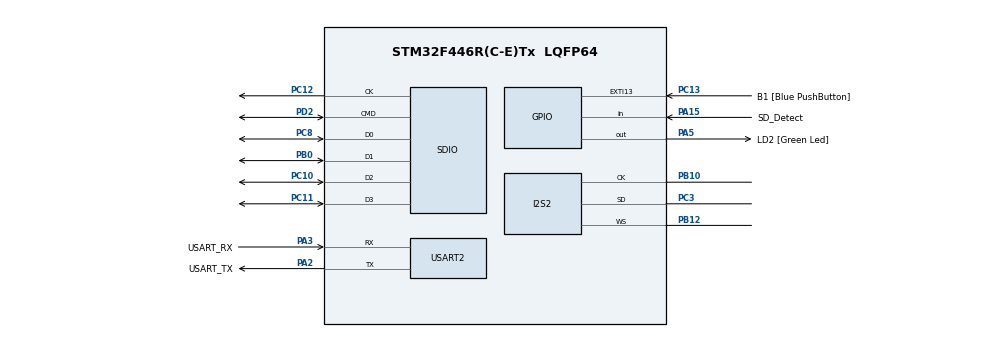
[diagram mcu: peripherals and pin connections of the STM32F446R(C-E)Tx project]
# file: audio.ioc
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Dma.Request0=SPI2_RX
Dma.Request1=USART2_TX
Dma.SPI2_RX.0.Direction=DMA_PERIPH_TO_MEMORY
Dma.SPI2_RX.0.FIFOMode=DMA_FIFOMODE_DISABLE
Dma.SPI2_RX.0.Instance=DMA1_Stream3
Dma.SPI2_RX.0.MemDataAlignment=DMA_MDATAALIGN_HALFWORD
Dma.SPI2_RX.0.MemInc=DMA_MINC_ENABLE
Dma.SPI2_RX.0.Mode=DMA_CIRCULAR
Dma.SPI2_RX.0.PeriphDataAlignment=DMA_PDATAALIGN_HALFWORD
Dma.SPI2_RX.0.PeriphInc=DMA_PINC_DISABLE
Dma.SPI2_RX.0.Priority=DMA_PRIORITY_LOW
Dma.USART2_TX.1.Direction=DMA_MEMORY_TO_PERIPH
Dma.USART2_TX.1.FIFOMode=DMA_FIFOMODE_DISABLE
Dma.USART2_TX.1.Instance=DMA1_Stream6
Dma.USART2_TX.1.MemDataAlignment=DMA_MDATAALIGN_HALFWORD
Dma.USART2_TX.1.MemInc=DMA_MINC_ENABLE
Dma.USART2_TX.1.Mode=DMA_CIRCULAR
Dma.USART2_TX.1.PeriphDataAlignment=DMA_PDATAALIGN_HALFWORD
Dma.USART2_TX.1.PeriphInc=DMA_PINC_DISABLE
Dma.USART2_TX.1.Priority=DMA_PRIORITY_LOW
FATFS.BSP.number=1
FATFS0.BSP.STBoard=false
FATFS0.BSP.api=Unknown
FATFS0.BSP.instance=PA15
FATFS0.BSP.ip=GPIO
FATFS0.BSP.mode=Input
FATFS0.BSP.name=Detect_SDIO
FATFS0.BSP.solution=PA15
I2S2.AudioFreq=I2S_AUDIOFREQ_32K
I2S2.DataFormat=I2S_DATAFORMAT_16B_EXTENDED
I2S2.ErrorAudioFreq=-0.26 %
I2S2.FullDuplexMode=I2S_FULLDUPLEXMODE_DISABLE
I2S2.Instance=SPI$Index
I2S2.Mode=I2S_MODE_MASTER_RX
I2S2.RealAudioFreq=31.914 KHz
I2S2.VirtualMode=I2S_MODE_MASTER
Mcu.Family=STM32F4
Mcu.Name=STM32F446R(C-E)Tx
Mcu.Package=LQFP64
NVIC.DMA1_Stream3_IRQn=true\:0\:0\:false\:false\:true\:false\:true\:true
NVIC.DMA1_Stream6_IRQn=true\:0\:0\:false\:false\:true\:false\:true\:true
NVIC.EXTI15_10_IRQn=true\:0\:0\:false\:false\:true\:true\:true\:true
NVIC.PriorityGroup=NVIC_PRIORITYGROUP_0
NVIC.USART2_IRQn=true\:0\:0\:false\:false\:true\:true\:true\:true
PA13.GPIO_Label=TMS
PA13.Mode=Serial_Wire
PA13.Signal=SYS_JTMS-SWDIO
PA14.GPIO_Label=TCK
PA14.Mode=Serial_Wire
PA14.Signal=SYS_JTCK-SWCLK
PA15.GPIO_Label=SD_Detect
PA15.Signal=GPIO_Input
PA2.GPIO_Label=USART_TX
PA2.Mode=Asynchronous
PA2.Signal=USART2_TX
PA3.GPIO_Label=USART_RX
PA3.Mode=Asynchronous
PA3.Signal=USART2_RX
PA5.GPIO_Label=LD2 [Green Led]
PA5.Signal=GPIO_Output
PB0.Mode=SD_4_bits_Wide_bus
PB0.Signal=SDIO_D1
PB10.Mode=Half_Duplex_Master
PB10.Signal=I2S2_CK
PB12.Mode=Half_Duplex_Master
PB12.Signal=I2S2_WS
PB3.GPIO_Label=SWO
PB3.Signal=SYS_JTDO-SWO
PC10.Mode=SD_4_bits_Wide_bus
PC10.Signal=SDIO_D2
PC11.Mode=SD_4_bits_Wide_bus
PC11.Signal=SDIO_D3
PC12.Mode=SD_4_bits_Wide_bus
PC12.Signal=SDIO_CK
PC13.GPIO_Label=B1 [Blue PushButton]
PC13.GPIO_ModeDefaultEXTI=GPIO_MODE_IT_RISING
PC13.Signal=GPXTI13
PC14-OSC32_IN.Mode=LSE-External-Oscillator
PC14-OSC32_IN.Signal=RCC_OSC32_IN
PC15-OSC32_OUT.Mode=LSE-External-Oscillator
PC15-OSC32_OUT.Signal=RCC_OSC32_OUT
PC3.Mode=Half_Duplex_Master
PC3.Signal=I2S2_SD
PC8.Mode=SD_4_bits_Wide_bus
PC8.Signal=SDIO_D0
PD2.Mode=SD_4_bits_Wide_bus
PD2.Signal=SDIO_CMD
PH0-OSC_IN.Mode=HSE-External-Oscillator
PH0-OSC_IN.Signal=RCC_OSC_IN
PH1-OSC_OUT.Mode=HSE-External-Oscillator
PH1-OSC_OUT.Signal=RCC_OSC_OUT
ProjectManager.HeapSize=0x200
ProjectManager.StackSize=0x400
ProjectManager.TargetToolchain=STM32CubeIDE
RCC.48MHZClocksFreq_Value=84000000
RCC.AHBFreq_Value=160000000
RCC.APB1CLKDivider=RCC_HCLK_DIV4
RCC.APB1Freq_Value=40000000
RCC.APB1TimFreq_Value=80000000
RCC.APB2CLKDivider=RCC_HCLK_DIV2
RCC.APB2Freq_Value=80000000
RCC.APB2TimFreq_Value=160000000
RCC.CortexFreq_Value=160000000
RCC.FLatency-AdvancedSettings=FLASH_LATENCY_5
RCC.HCLKFreq_Value=160000000
RCC.HSE_VALUE=8000000
RCC.HSI_VALUE=16000000
RCC.PLLM=8
RCC.PLLN=160
RCC.PLLQ=7
RCC.SYSCLKFreq_VALUE=160000000
RCC.SYSCLKSource=RCC_SYSCLKSOURCE_PLLCLK
RCC.USBFreq_Value=45714285.71428572
RCC.VCOOutputFreq_Value=320000000
SDIO.ClockDiv=8
STMicroelectronics.X-CUBE-ALGOBUILD.1.3.0.LibraryCcDSPOoLibraryJjDSPOoLibrary=true
USART2.VirtualMode=VM_ASYNC
VP_FATFS_VS_SDIO.Mode=SDIO
VP_STMicroelectronics.X-CUBE-ALGOBUILD_VS_DSPOoLibraryJjLibrary_1.3.0_1.3.0.Mode=DSPOoLibraryJjLibrary
board=NUCLEO-F446RE

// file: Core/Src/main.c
/* USER CODE BEGIN Header */
/**
  ******************************************************************************
  * @file           : main.c
  * @brief          : Main program body
  ******************************************************************************
  * @attention
  *
  * Copyright (c) 2022 STMicroelectronics.
  * All rights reserved.
  *
  * This software is licensed under terms that can be found in the LICENSE file
  * in the root directory of this software component.
  * If no LICENSE file comes with this software, it is provided AS-IS.
  *
  ******************************************************************************
  */
/* USER CODE END Header */
#include "main.h"
#include "fatfs.h"

/* USER CODE BEGIN Includes */
#include "stdio.h"

#include "arm_math.h"
#include "audio_sd.h"
/* USER CODE END Includes */

 I2S_HandleTypeDef hi2s2;
DMA_HandleTypeDef hdma_spi2_rx;

SD_HandleTypeDef hsd;

UART_HandleTypeDef huart2;
DMA_HandleTypeDef hdma_usart2_tx;

/* USER CODE BEGIN PV */
int16_t data_i2s[WAV_WRITE_SAMPLE_COUNT];
float32_t mic1_data1[WAV_WRITE_SAMPLE_COUNT / 4],
	mic1_data2[WAV_WRITE_SAMPLE_COUNT / 4];
float32_t data_out_fft1[WAV_WRITE_SAMPLE_COUNT / 4],
	data_out_fft2[WAV_WRITE_SAMPLE_COUNT / 4];
volatile int16_t sample_i2s;
volatile uint8_t button_flag, start_stop_recording;
volatile uint8_t  half_i2s, full_i2s;
arm_rfft_fast_instance_f32 fft_audio_instance;
/* USER CODE END PV */

void SystemClock_Config(void);
static void MX_GPIO_Init(void);
static void MX_DMA_Init(void);
static void MX_I2S2_Init(void);
static void MX_SDIO_SD_Init(void);
static void MX_USART2_UART_Init(void);

int main(void)
{
  /* USER CODE BEGIN 1 */
uint8_t uart_counter;
  /* USER CODE END 1 */

  /* MCU Configuration--------------------------------------------------------*/

  /* Reset of all peripherals, Initializes the Flash interface and the Systick. */
  HAL_Init();

  /* Configure the system clock */
  SystemClock_Config();

  /* Initialize all configured peripherals */
  MX_GPIO_Init();
  MX_DMA_Init();
  MX_I2S2_Init();
  MX_SDIO_SD_Init();
  MX_FATFS_Init();
  MX_USART2_UART_Init();
  /* USER CODE BEGIN 2 */
  HAL_I2S_DMAStop(&hi2s2);
  HAL_Delay(500);
  //	Initializing FFT. We apply FFT for the first microphone and half of the buffer.
  //	Therefore we divide by four: WAV_WRITE_SAMPLE_COUNT / 4
  arm_rfft_fast_init_f32(&fft_audio_instance, WAV_WRITE_SAMPLE_COUNT / 4);
  /* USER CODE END 2 */

  /* Infinite loop */
  /* USER CODE BEGIN WHILE */
  while (1)
  {
	  // when button is pressed
	  if(button_flag)
	  {
		  //	stop recording: stop I2S DMA
		  if(start_stop_recording)
		  {
			  HAL_I2S_DMAStop(&hi2s2);
			  start_stop_recording = 0;
			  half_i2s = 0;
			  full_i2s = 0;
			  printf("stop recording \n");
		  }

		  // start recording: start DMA
		  else
		  {
			  start_stop_recording = 1;
			  printf("start_recording");
			  HAL_I2S_Receive_DMA(&hi2s2, (uint16_t *)data_i2s, sizeof(data_i2s)/2);
		  }
		  button_flag = 0;
	  }
    /* USER CODE END WHILE */

    /* USER CODE BEGIN 3 */
	  // When half of the buffer is full
	  if(start_stop_recording == 1 && half_i2s == 1)
	  {
		  // extracting the data of the first microphone
		  for(int i = 0; i < WAV_WRITE_SAMPLE_COUNT / 4; i++ )
		  {
			  mic1_data1[i] = (float32_t)data_i2s[i * 2];
		  }
		  // apply FFT
		  arm_rfft_fast_f32(&fft_audio_instance, mic1_data1, data_out_fft1, 0);
		  // extract absolute values by computing the magnitude of the complex numbers
		  // Pay attention that after this operation, half of the buffer possesses the magnitudes
		  arm_cmplx_mag_f32(
				  data_out_fft1,
				  data_out_fft1,
				  WAV_WRITE_SAMPLE_COUNT / 8);
		  // bias removal
		  data_out_fft1[0] = 0;
		  if(full_i2s == 1)
		  {
			  printf("d \n");
		  }
		  uart_counter++;
		  //	setting ">>>>" to indicate the end of the buffer
	  	  data_out_fft1[WAV_WRITE_SAMPLE_COUNT / 8] = ('>'<<24|'>'<<16|'>'<<8|'>');

	  if (uart_counter == 30)
		  {
			  printf("uart start\n");
			  uart_counter = 0;
			  //	sending only half of the buffer
			  HAL_UART_Transmit_DMA(&huart2, (uint8_t *)&data_out_fft1, sizeof(data_out_fft1) / 2 + 4);
		  }
		  half_i2s = 0;
	  }

	  //	THe buffer is full
	  if(start_stop_recording == 1 && full_i2s == 1)
	  {
		  // extracting the data of the first microphone
		  for(int i = 0; i < WAV_WRITE_SAMPLE_COUNT / 4; i++ )
		  {
			  mic1_data2[i] = (float32_t)data_i2s[i * 2 +
												WAV_WRITE_SAMPLE_COUNT / 2];
		  }
		  // applying FFT
		  arm_rfft_fast_f32(&fft_audio_instance, mic1_data2, data_out_fft2, 0);
		  // extract absolute values by computing the magnitude of the complex numbers
		  // Pay attention that after this operation, half of the buffer possesses the magnitudes
		  arm_cmplx_mag_f32(
				  data_out_fft2,
				  data_out_fft2,
				  WAV_WRITE_SAMPLE_COUNT / 8);
		  // bias removal
		  data_out_fft2[0] = 0;
		  if(half_i2s == 1)
		  {
			  printf("d \n");
		  }
		  full_i2s = 0;
	  }
  }
  /* USER CODE END 3 */
}

void SystemClock_Config(void)
{
  RCC_OscInitTypeDef RCC_OscInitStruct = {0};
  RCC_ClkInitTypeDef RCC_ClkInitStruct = {0};

  /** Configure the main internal regulator output voltage
  */
  __HAL_RCC_PWR_CLK_ENABLE();
  __HAL_PWR_VOLTAGESCALING_CONFIG(PWR_REGULATOR_VOLTAGE_SCALE1);

  /** Initializes the RCC Oscillators according to the specified parameters
  * in the RCC_OscInitTypeDef structure.
  */
  RCC_OscInitStruct.OscillatorType = RCC_OSCILLATORTYPE_HSI;
  RCC_OscInitStruct.HSIState = RCC_HSI_ON;
  RCC_OscInitStruct.HSICalibrationValue = RCC_HSICALIBRATION_DEFAULT;
  RCC_OscInitStruct.PLL.PLLState = RCC_PLL_ON;
  RCC_OscInitStruct.PLL.PLLSource = RCC_PLLSOURCE_HSI;
  RCC_OscInitStruct.PLL.PLLM = 8;
  RCC_OscInitStruct.PLL.PLLN = 168;
  RCC_OscInitStruct.PLL.PLLP = RCC_PLLP_DIV2;
  RCC_OscInitStruct.PLL.PLLQ = 7;
  if (HAL_RCC_OscConfig(&RCC_OscInitStruct) != HAL_OK)
  {
    Error_Handler();
  }

  /** Initializes the CPU, AHB and APB buses clocks
  */
  RCC_ClkInitStruct.ClockType = RCC_CLOCKTYPE_HCLK|RCC_CLOCKTYPE_SYSCLK
                              |RCC_CLOCKTYPE_PCLK1|RCC_CLOCKTYPE_PCLK2;
  RCC_ClkInitStruct.SYSCLKSource = RCC_SYSCLKSOURCE_PLLCLK;
  RCC_ClkInitStruct.AHBCLKDivider = RCC_SYSCLK_DIV1;
  RCC_ClkInitStruct.APB1CLKDivider = RCC_HCLK_DIV4;
  RCC_ClkInitStruct.APB2CLKDivider = RCC_HCLK_DIV2;

  if (HAL_RCC_ClockConfig(&RCC_ClkInitStruct, FLASH_LATENCY_5) != HAL_OK)
  {
    Error_Handler();
  }
}

static void MX_I2S2_Init(void)
{

  hi2s2.Instance = SPI2;
  hi2s2.Init.Mode = I2S_MODE_MASTER_RX;
  hi2s2.Init.Standard = I2S_STANDARD_PHILIPS;
  hi2s2.Init.DataFormat = I2S_DATAFORMAT_16B_EXTENDED;
  hi2s2.Init.MCLKOutput = I2S_MCLKOUTPUT_DISABLE;
  hi2s2.Init.AudioFreq = I2S_AUDIOFREQ_32K;
  hi2s2.Init.CPOL = I2S_CPOL_LOW;
  hi2s2.Init.ClockSource = I2S_CLOCK_PLL;
  hi2s2.Init.FullDuplexMode = I2S_FULLDUPLEXMODE_DISABLE;
  if (HAL_I2S_Init(&hi2s2) != HAL_OK)
  {
    Error_Handler();
  }

}

static void MX_SDIO_SD_Init(void)
{

  hsd.Instance = SDIO;
  hsd.Init.ClockEdge = SDIO_CLOCK_EDGE_RISING;
  hsd.Init.ClockBypass = SDIO_CLOCK_BYPASS_DISABLE;
  hsd.Init.ClockPowerSave = SDIO_CLOCK_POWER_SAVE_DISABLE;
  hsd.Init.BusWide = SDIO_BUS_WIDE_1B;
  hsd.Init.HardwareFlowControl = SDIO_HARDWARE_FLOW_CONTROL_DISABLE;
  hsd.Init.ClockDiv = 8;

}

static void MX_USART2_UART_Init(void)
{

  huart2.Instance = USART2;
  huart2.Init.BaudRate = 115200;
  huart2.Init.WordLength = UART_WORDLENGTH_8B;
  huart2.Init.StopBits = UART_STOPBITS_1;
  huart2.Init.Parity = UART_PARITY_NONE;
  huart2.Init.Mode = UART_MODE_TX_RX;
  huart2.Init.HwFlowCtl = UART_HWCONTROL_NONE;
  huart2.Init.OverSampling = UART_OVERSAMPLING_16;
  if (HAL_UART_Init(&huart2) != HAL_OK)
  {
    Error_Handler();
  }

}

static void MX_DMA_Init(void)
{

  /* DMA controller clock enable */
  __HAL_RCC_DMA1_CLK_ENABLE();

  /* DMA interrupt init */
  /* DMA1_Stream3_IRQn interrupt configuration */
  HAL_NVIC_SetPriority(DMA1_Stream3_IRQn, 0, 0);
  HAL_NVIC_EnableIRQ(DMA1_Stream3_IRQn);
  /* DMA1_Stream6_IRQn interrupt configuration */
  HAL_NVIC_SetPriority(DMA1_Stream6_IRQn, 0, 0);
  HAL_NVIC_EnableIRQ(DMA1_Stream6_IRQn);

}

static void MX_GPIO_Init(void)
{
  GPIO_InitTypeDef GPIO_InitStruct = {0};

  /* GPIO Ports Clock Enable */
  __HAL_RCC_GPIOE_CLK_ENABLE();
  __HAL_RCC_GPIOC_CLK_ENABLE();
  __HAL_RCC_GPIOH_CLK_ENABLE();
  __HAL_RCC_GPIOA_CLK_ENABLE();
  __HAL_RCC_GPIOB_CLK_ENABLE();
  __HAL_RCC_GPIOD_CLK_ENABLE();

  /*Configure GPIO pin Output Level */
  HAL_GPIO_WritePin(CS_I2C_SPI_GPIO_Port, CS_I2C_SPI_Pin, GPIO_PIN_RESET);

  /*Configure GPIO pin Output Level */
  HAL_GPIO_WritePin(OTG_FS_PowerSwitchOn_GPIO_Port, OTG_FS_PowerSwitchOn_Pin, GPIO_PIN_SET);

  /*Configure GPIO pin Output Level */
  HAL_GPIO_WritePin(GPIOD, LD4_Pin|LD3_Pin|LD5_Pin|LD6_Pin
                          |Audio_RST_Pin, GPIO_PIN_RESET);

  /*Configure GPIO pin : CS_I2C_SPI_Pin */
  GPIO_InitStruct.Pin = CS_I2C_SPI_Pin;
  GPIO_InitStruct.Mode = GPIO_MODE_OUTPUT_PP;
  GPIO_InitStruct.Pull = GPIO_NOPULL;
  GPIO_InitStruct.Speed = GPIO_SPEED_FREQ_LOW;
  HAL_GPIO_Init(CS_I2C_SPI_GPIO_Port, &GPIO_InitStruct);

  /*Configure GPIO pin : OTG_FS_PowerSwitchOn_Pin */
  GPIO_InitStruct.Pin = OTG_FS_PowerSwitchOn_Pin;
  GPIO_InitStruct.Mode = GPIO_MODE_OUTPUT_PP;
  GPIO_InitStruct.Pull = GPIO_NOPULL;
  GPIO_InitStruct.Speed = GPIO_SPEED_FREQ_LOW;
  HAL_GPIO_Init(OTG_FS_PowerSwitchOn_GPIO_Port, &GPIO_InitStruct);

  /*Configure GPIO pin : B1_Pin */
  GPIO_InitStruct.Pin = B1_Pin;
  GPIO_InitStruct.Mode = GPIO_MODE_IT_RISING;
  GPIO_InitStruct.Pull = GPIO_NOPULL;
  HAL_GPIO_Init(B1_GPIO_Port, &GPIO_InitStruct);

  /*Configure GPIO pin : I2S3_WS_Pin */
  GPIO_InitStruct.Pin = I2S3_WS_Pin;
  GPIO_InitStruct.Mode = GPIO_MODE_AF_PP;
  GPIO_InitStruct.Pull = GPIO_NOPULL;
  GPIO_InitStruct.Speed = GPIO_SPEED_FREQ_LOW;
  GPIO_InitStruct.Alternate = GPIO_AF6_SPI3;
  HAL_GPIO_Init(I2S3_WS_GPIO_Port, &GPIO_InitStruct);

  /*Configure GPIO pins : SPI1_SCK_Pin SPI1_MISO_Pin SPI1_MOSI_Pin */
  GPIO_InitStruct.Pin = SPI1_SCK_Pin|SPI1_MISO_Pin|SPI1_MOSI_Pin;
  GPIO_InitStruct.Mode = GPIO_MODE_AF_PP;
  GPIO_InitStruct.Pull = GPIO_NOPULL;
  GPIO_InitStruct.Speed = GPIO_SPEED_FREQ_LOW;
  GPIO_InitStruct.Alternate = GPIO_AF5_SPI1;
  HAL_GPIO_Init(GPIOA, &GPIO_InitStruct);

  /*Configure GPIO pin : BOOT1_Pin */
  GPIO_InitStruct.Pin = BOOT1_Pin;
  GPIO_InitStruct.Mode = GPIO_MODE_INPUT;
  GPIO_InitStruct.Pull = GPIO_NOPULL;
  HAL_GPIO_Init(BOOT1_GPIO_Port, &GPIO_InitStruct);

  /*Configure GPIO pins : LD4_Pin LD3_Pin LD5_Pin LD6_Pin
                           Audio_RST_Pin */
  GPIO_InitStruct.Pin = LD4_Pin|LD3_Pin|LD5_Pin|LD6_Pin
                          |Audio_RST_Pin;
  GPIO_InitStruct.Mode = GPIO_MODE_OUTPUT_PP;
  GPIO_InitStruct.Pull = GPIO_NOPULL;
  GPIO_InitStruct.Speed = GPIO_SPEED_FREQ_LOW;
  HAL_GPIO_Init(GPIOD, &GPIO_InitStruct);

  /*Configure GPIO pin : I2S3_MCK_Pin */
  GPIO_InitStruct.Pin = I2S3_MCK_Pin;
  GPIO_InitStruct.Mode = GPIO_MODE_AF_PP;
  GPIO_InitStruct.Pull = GPIO_NOPULL;
  GPIO_InitStruct.Speed = GPIO_SPEED_FREQ_LOW;
  GPIO_InitStruct.Alternate = GPIO_AF6_SPI3;
  HAL_GPIO_Init(I2S3_MCK_GPIO_Port, &GPIO_InitStruct);

  /*Configure GPIO pin : VBUS_FS_Pin */
  GPIO_InitStruct.Pin = VBUS_FS_Pin;
  GPIO_InitStruct.Mode = GPIO_MODE_INPUT;
  GPIO_InitStruct.Pull = GPIO_NOPULL;
  HAL_GPIO_Init(VBUS_FS_GPIO_Port, &GPIO_InitStruct);

  /*Configure GPIO pins : OTG_FS_ID_Pin OTG_FS_DM_Pin OTG_FS_DP_Pin */
  GPIO_InitStruct.Pin = OTG_FS_ID_Pin|OTG_FS_DM_Pin|OTG_FS_DP_Pin;
  GPIO_InitStruct.Mode = GPIO_MODE_AF_PP;
  GPIO_InitStruct.Pull = GPIO_NOPULL;
  GPIO_InitStruct.Speed = GPIO_SPEED_FREQ_LOW;
  GPIO_InitStruct.Alternate = GPIO_AF10_OTG_FS;
  HAL_GPIO_Init(GPIOA, &GPIO_InitStruct);

  /*Configure GPIO pins : SD_Detect_Pin OTG_FS_OverCurrent_Pin */
  GPIO_InitStruct.Pin = SD_Detect_Pin|OTG_FS_OverCurrent_Pin;
  GPIO_InitStruct.Mode = GPIO_MODE_INPUT;
  GPIO_InitStruct.Pull = GPIO_NOPULL;
  HAL_GPIO_Init(GPIOD, &GPIO_InitStruct);

  /*Configure GPIO pins : Audio_SCL_Pin Audio_SDA_Pin */
  GPIO_InitStruct.Pin = Audio_SCL_Pin|Audio_SDA_Pin;
  GPIO_InitStruct.Mode = GPIO_MODE_AF_OD;
  GPIO_InitStruct.Pull = GPIO_NOPULL;
  GPIO_InitStruct.Speed = GPIO_SPEED_FREQ_LOW;
  GPIO_InitStruct.Alternate = GPIO_AF4_I2C1;
  HAL_GPIO_Init(GPIOB, &GPIO_InitStruct);

  /*Configure GPIO pin : MEMS_INT2_Pin */
  GPIO_InitStruct.Pin = MEMS_INT2_Pin;
  GPIO_InitStruct.Mode = GPIO_MODE_EVT_RISING;
  GPIO_InitStruct.Pull = GPIO_NOPULL;
  HAL_GPIO_Init(MEMS_INT2_GPIO_Port, &GPIO_InitStruct);

  /* EXTI interrupt init*/
  HAL_NVIC_SetPriority(EXTI0_IRQn, 0, 0);
  HAL_NVIC_EnableIRQ(EXTI0_IRQn);

}

/* USER CODE BEGIN 4 */
int _write(int file, char *ptr, int len)
{
	int DataIdx;

	for (DataIdx = 0; DataIdx < len; DataIdx++)
	{
		ITM_SendChar(*ptr++);
	}
	return len;
}
//	l,r,l,r,l,
void HAL_I2S_RxCpltCallback(I2S_HandleTypeDef *hi2s)
{

	full_i2s = 1;
}
void HAL_I2S_RxHalfCpltCallback(I2S_HandleTypeDef *hi2s)
{
	//sample_i2s = data_i2s[0];
	half_i2s = 1;
}

void HAL_GPIO_EXTI_Callback(uint16_t GPIO_Pin)
{
	if(GPIO_Pin == B1_Pin)
	{
		button_flag = 1;
	}
}

void HAL_UART_TxCpltCallback(UART_HandleTypeDef *huart)
{
	printf("uart over \n");
}
/* USER CODE END 4 */

void Error_Handler(void)
{
  __disable_irq();
  while (1)
  {
  }
}
